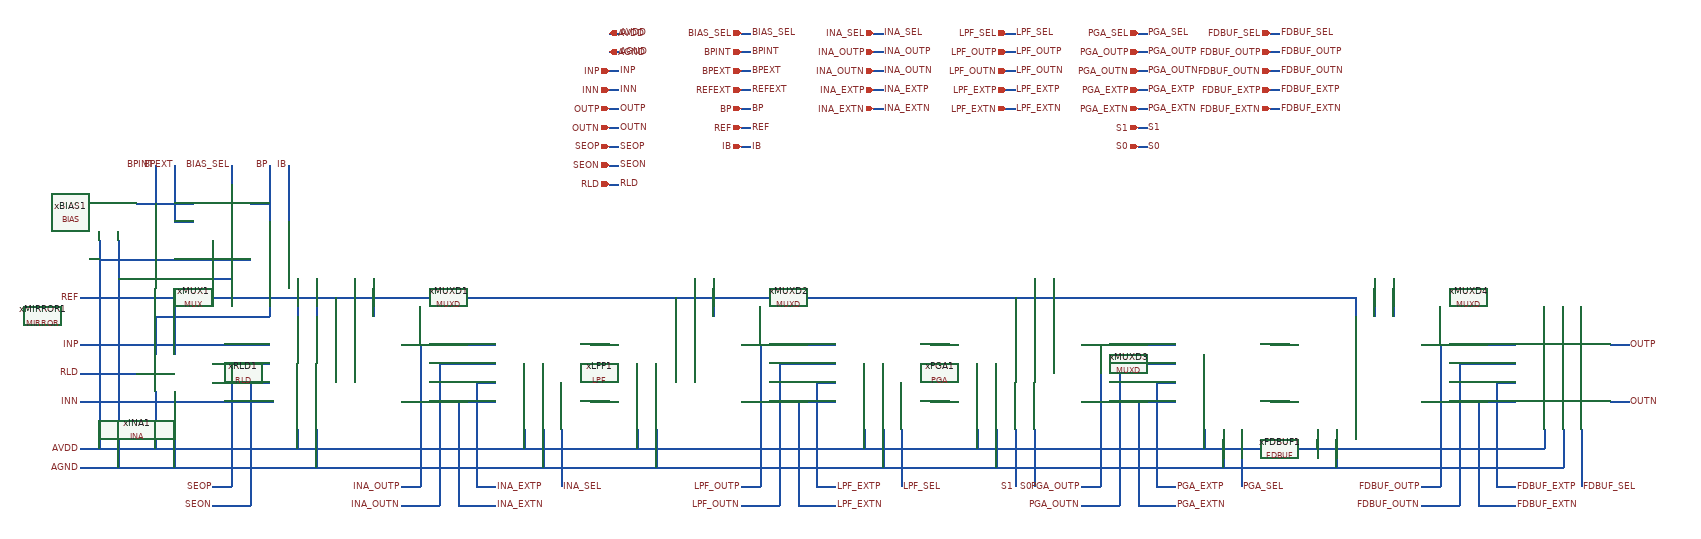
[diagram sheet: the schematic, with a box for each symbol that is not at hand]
v {xschem version=3.4.8RC file_version=1.3}
G {}
K {}
V {}
S {}
F {}
E {}
N 1880 -540 1920 -540 {lab=#net1}
N 1880 -420 1920 -420 {lab=#net2}
N 1160 -420 1200 -420 {lab=#net3}
N 1160 -540 1200 -540 {lab=#net4}
N 2600 -420 2640 -420 {lab=#net5}
N 2600 -540 2640 -540 {lab=#net6}
N 540 -360 540 -320 {lab=AVDD}
N 580 -360 580 -280 {lab=AGND}
N 2960 -540 2960 -240 {lab=FDBUF_OUTP}
N 2920 -420 3000 -420 {lab=FDBUF_OUTN}
N 3000 -500 3120 -500 {lab=FDBUF_OUTN}
N 3000 -500 3000 -200 {lab=FDBUF_OUTN}
N 2920 -540 3120 -540 {lab=FDBUF_OUTP}
N 2240 -540 2240 -240 {lab=PGA_OUTP}
N 2200 -420 2280 -420 {lab=PGA_OUTN}
N 2280 -500 2400 -500 {lab=PGA_OUTN}
N 2280 -500 2280 -200 {lab=PGA_OUTN}
N 2200 -540 2400 -540 {lab=PGA_OUTP}
N 1520 -540 1520 -240 {lab=LPF_OUTP}
N 1480 -420 1560 -420 {lab=LPF_OUTN}
N 1560 -500 1680 -500 {lab=LPF_OUTN}
N 1560 -500 1560 -200 {lab=LPF_OUTN}
N 1480 -540 1680 -540 {lab=LPF_OUTP}
N 800 -540 800 -240 {lab=INA_OUTP}
N 760 -420 840 -420 {lab=INA_OUTN}
N 840 -500 840 -200 {lab=INA_OUTN}
N 540 -680 540 -600 {lab=#net7}
N 580 -680 580 -600 {lab=#net8}
N 620 -640 620 -600 {lab=REF}
N 660 -680 660 -600 {lab=#net9}
N 700 -680 700 -600 {lab=#net10}
N 2780 -640 2780 -600 {lab=REF}
N 1340 -640 1340 -600 {lab=REF}
N 1380 -680 1380 -600 {lab=#net11}
N 1420 -680 1420 -600 {lab=#net12}
N 2100 -680 2100 -600 {lab=#net13}
N 2140 -680 2140 -600 {lab=#net14}
N 2060 -640 2060 -600 {lab=REF}
N 3220 -360 3220 -280 {lab=AGND}
N 3180 -360 3180 -320 {lab=AVDD}
N 1300 -360 1300 -280 {lab=AGND}
N 1060 -360 1060 -280 {lab=AGND}
N 1020 -360 1020 -320 {lab=AVDD}
N 1260 -360 1260 -320 {lab=AVDD}
N 1100 -360 1100 -240 {lab=INA_SEL}
N 1780 -360 1780 -280 {lab=AGND}
N 1740 -360 1740 -320 {lab=AVDD}
N 1820 -360 1820 -240 {lab=LPF_SEL}
N 2500 -360 2500 -280 {lab=AGND}
N 2460 -360 2460 -320 {lab=AVDD}
N 2540 -360 2540 -240 {lab=PGA_SEL}
N 3260 -360 3260 -240 {lab=FDBUF_SEL}
N 2740 -360 2740 -280 {lab=AGND}
N 2700 -360 2700 -320 {lab=AVDD}
N 2020 -360 2020 -280 {lab=AGND}
N 1980 -360 1980 -320 {lab=AVDD}
N 2060 -360 2060 -240 {lab=S1}
N 2100 -360 2100 -240 {lab=S0}
N 3320 -420 3360 -420 {lab=OUTN}
N 3320 -540 3360 -540 {lab=OUTP}
N 80 -280 3220 -280 {lab=AGND}
N 80 -320 3180 -320 {lab=AVDD}
N 360 -460 480 -460 {lab=SEON}
N 360 -500 480 -500 {lab=SEOP}
N 400 -500 400 -240 {lab=SEOP}
N 280 -640 280 -520 {lab=REF}
N 80 -640 2780 -640 {lab=REF}
N 240 -920 240 -840 {lab=BPINT}
N 280 -800 320 -800 {lab=BPEXT}
N 280 -920 280 -800 {lab=BPEXT}
N 200 -840 320 -840 {lab=BPINT}
N 2820 -680 2820 -600 {lab=#net15}
N 2860 -680 2860 -600 {lab=#net16}
N 360 -760 360 -720 {lab=AVDD}
N 400 -760 400 -680 {lab=AGND}
N 480 -920 480 -800 {lab=BP}
N 160 -680 400 -680 {lab=AGND}
N 120 -720 440 -720 {lab=AVDD}
N 120 -760 120 -320 {lab=AVDD}
N 160 -760 160 -280 {lab=AGND}
N 240 -440 240 -320 {lab=AVDD}
N 280 -440 280 -280 {lab=AGND}
N 1760 -1160 1780 -1160 {lab=INA_OUTP}
N 1760 -1120 1780 -1120 {lab=INA_OUTN}
N 1760 -1080 1780 -1080 {lab=INA_EXTP}
N 1760 -1040 1780 -1040 {lab=INA_EXTN}
N 2040 -1160 2060 -1160 {lab=LPF_OUTP}
N 2040 -1120 2060 -1120 {lab=LPF_OUTN}
N 2040 -1080 2060 -1080 {lab=LPF_EXTP}
N 2040 -1040 2060 -1040 {lab=LPF_EXTN}
N 2320 -1160 2340 -1160 {lab=PGA_OUTP}
N 2320 -1120 2340 -1120 {lab=PGA_OUTN}
N 2320 -1080 2340 -1080 {lab=PGA_EXTP}
N 2320 -1040 2340 -1040 {lab=PGA_EXTN}
N 2600 -1160 2620 -1160 {lab=FDBUF_OUTP}
N 2600 -1120 2620 -1120 {lab=FDBUF_OUTN}
N 2600 -1080 2620 -1080 {lab=FDBUF_EXTP}
N 2600 -1040 2620 -1040 {lab=FDBUF_EXTN}
N 1200 -1200 1220 -1200 {lab=AVDD}
N 1200 -1160 1220 -1160 {lab=AGND}
N 1200 -960 1220 -960 {lab=SEOP}
N 1200 -920 1220 -920 {lab=SEON}
N 1200 -880 1220 -880 {lab=RLD}
N 1200 -1120 1220 -1120 {lab=INP}
N 1200 -1080 1220 -1080 {lab=INN}
N 1480 -1160 1500 -1160 {lab=BPINT}
N 1480 -1120 1500 -1120 {lab=BPEXT}
N 1480 -1080 1500 -1080 {lab=REFEXT}
N 1480 -1200 1500 -1200 {lab=BIAS_SEL}
N 1480 -1040 1500 -1040 {lab=BP}
N 1480 -1000 1500 -1000 {lab=REF}
N 1760 -1200 1780 -1200 {lab=INA_SEL}
N 2040 -1200 2060 -1200 {lab=LPF_SEL}
N 2320 -1200 2340 -1200 {lab=PGA_SEL}
N 2320 -1000 2340 -1000 {lab=S1}
N 2320 -960 2340 -960 {lab=S0}
N 2600 -1200 2620 -1200 {lab=FDBUF_SEL}
N 1200 -1040 1220 -1040 {lab=OUTP}
N 1200 -1000 1220 -1000 {lab=OUTN}
N 1480 -960 1500 -960 {lab=IB}
N 520 -920 520 -800 {lab=IB}
N 400 -920 400 -880 {lab=BIAS_SEL}
N 80 -540 480 -540 {lab=INP}
N 80 -480 200 -480 {lab=RLD}
N 80 -420 490 -420 {lab=INN}
N 880 -420 880 -200 {lab=INA_EXTN}
N 920 -460 920 -240 {lab=INA_EXTP}
N 760 -540 960 -540 {lab=INA_OUTP}
N 840 -500 960 -500 {lab=INA_OUTN}
N 760 -240 800 -240 {lab=INA_OUTP}
N 760 -200 840 -200 {lab=INA_OUTN}
N 880 -420 960 -420 {lab=INA_EXTN}
N 920 -460 960 -460 {lab=INA_EXTP}
N 880 -200 960 -200 {lab=INA_EXTN}
N 920 -240 960 -240 {lab=INA_EXTP}
N 1480 -240 1520 -240 {lab=LPF_OUTP}
N 1480 -200 1560 -200 {lab=LPF_OUTN}
N 1600 -420 1680 -420 {lab=LPF_EXTN}
N 1600 -420 1600 -200 {lab=LPF_EXTN}
N 1600 -200 1680 -200 {lab=LPF_EXTN}
N 1640 -240 1680 -240 {lab=LPF_EXTP}
N 1640 -460 1640 -240 {lab=LPF_EXTP}
N 1640 -460 1680 -460 {lab=LPF_EXTP}
N 2200 -240 2240 -240 {lab=PGA_OUTP}
N 2200 -200 2280 -200 {lab=PGA_OUTN}
N 2360 -460 2400 -460 {lab=PGA_EXTP}
N 2360 -460 2360 -240 {lab=PGA_EXTP}
N 2360 -240 2400 -240 {lab=PGA_EXTP}
N 2320 -200 2400 -200 {lab=PGA_EXTN}
N 2320 -420 2320 -200 {lab=PGA_EXTN}
N 2320 -420 2400 -420 {lab=PGA_EXTN}
N 2920 -240 2960 -240 {lab=FDBUF_OUTP}
N 2920 -200 3000 -200 {lab=FDBUF_OUTN}
N 3080 -460 3120 -460 {lab=FDBUF_EXTP}
N 3080 -460 3080 -240 {lab=FDBUF_EXTP}
N 3080 -240 3120 -240 {lab=FDBUF_EXTP}
N 3040 -200 3120 -200 {lab=FDBUF_EXTN}
N 3040 -420 3040 -200 {lab=FDBUF_EXTN}
N 3040 -420 3120 -420 {lab=FDBUF_EXTN}
N 480 -680 480 -600 {lab=#net17}
N 240 -600 480 -600 {lab=#net17}
N 240 -600 240 -520 {lab=#net17}
N 440 -840 480 -840 {lab=BP}
N 360 -240 400 -240 {lab=SEOP}
N 360 -200 440 -200 {lab=SEON}
N 440 -460 440 -200 {lab=SEON}
C {title.sym} 160 -40 0 0 {name=l1 author="Yi-Hsiang Wei"}
C {lab_wire.sym} 80 -540 0 0 {name=p6 sig_type=std_logic lab=INP}
C {lab_wire.sym} 80 -420 0 0 {name=p7 sig_type=std_logic lab=INN}
C {lab_wire.sym} 3360 -540 0 1 {name=p20 sig_type=std_logic lab=OUTP}
C {lab_wire.sym} 3360 -420 0 1 {name=p21 sig_type=std_logic lab=OUTN}
C {ECG_Acquisition_IC/Design_Files/IC Design/Schematic/AFE_BLOCKS/LPF/LPF.sym} 1140 -320 0 0 {name=xLFP1}
C {ECG_Acquisition_IC/Design_Files/IC Design/Schematic/AFE_BLOCKS/PGA/PGA.sym} 1860 -320 0 0 {name=xPGA1}
C {ECG_Acquisition_IC/Design_Files/IC Design/Schematic/DIGITAL_BLOCKS/MUXD/MUXD.sym} 900 -320 0 0 {name=xMUXD1}
C {ECG_Acquisition_IC/Design_Files/IC Design/Schematic/AFE_BLOCKS/INA/INA.sym} 420 -320 0 0 {name=xINA1}
C {ECG_Acquisition_IC/Design_Files/IC Design/Schematic/DIGITAL_BLOCKS/MUXD/MUXD.sym} 1620 -320 0 0 {name=xMUXD2}
C {ECG_Acquisition_IC/Design_Files/IC Design/Schematic/DIGITAL_BLOCKS/MUXD/MUXD.sym} 2340 -320 0 0 {name=xMUXD3}
C {ECG_Acquisition_IC/Design_Files/IC Design/Schematic/DIGITAL_BLOCKS/MUXD/MUXD.sym} 3060 -320 0 0 {name=xMUXD4}
C {lab_wire.sym} 360 -240 0 0 {name=p94 sig_type=std_logic lab=SEOP}
C {lab_wire.sym} 360 -200 0 0 {name=p95 sig_type=std_logic lab=SEON}
C {lab_wire.sym} 760 -240 0 0 {name=p38 sig_type=std_logic lab=INA_OUTP}
C {lab_wire.sym} 760 -200 0 0 {name=p43 sig_type=std_logic lab=INA_OUTN}
C {lab_wire.sym} 1100 -240 2 0 {name=p46 sig_type=std_logic lab=INA_SEL}
C {lab_wire.sym} 1480 -240 0 0 {name=p47 sig_type=std_logic lab=LPF_OUTP}
C {lab_wire.sym} 1480 -200 0 0 {name=p48 sig_type=std_logic lab=LPF_OUTN}
C {lab_wire.sym} 960 -240 0 1 {name=p49 sig_type=std_logic lab=INA_EXTP}
C {lab_wire.sym} 960 -200 0 1 {name=p51 sig_type=std_logic lab=INA_EXTN}
C {lab_wire.sym} 2200 -240 0 0 {name=p62 sig_type=std_logic lab=PGA_OUTP}
C {lab_wire.sym} 2200 -200 0 0 {name=p67 sig_type=std_logic lab=PGA_OUTN}
C {lab_wire.sym} 1680 -240 0 1 {name=p70 sig_type=std_logic lab=LPF_EXTP}
C {lab_wire.sym} 1680 -200 0 1 {name=p80 sig_type=std_logic lab=LPF_EXTN}
C {lab_wire.sym} 1820 -240 2 0 {name=p82 sig_type=std_logic lab=LPF_SEL}
C {lab_wire.sym} 2060 -240 2 1 {name=p83 sig_type=std_logic lab=S1}
C {lab_wire.sym} 2100 -240 2 1 {name=p84 sig_type=std_logic lab=S0}
C {lab_wire.sym} 2540 -240 2 0 {name=p85 sig_type=std_logic lab=PGA_SEL}
C {lab_wire.sym} 3260 -240 2 0 {name=p87 sig_type=std_logic lab=FDBUF_SEL}
C {lab_wire.sym} 2920 -240 0 0 {name=p92 sig_type=std_logic lab=FDBUF_OUTP}
C {lab_wire.sym} 2920 -200 0 0 {name=p93 sig_type=std_logic lab=FDBUF_OUTN}
C {lab_wire.sym} 2400 -240 0 1 {name=p100 sig_type=std_logic lab=PGA_EXTP}
C {lab_wire.sym} 2400 -200 0 1 {name=p101 sig_type=std_logic lab=PGA_EXTN}
C {lab_wire.sym} 3120 -240 0 1 {name=p132 sig_type=std_logic lab=FDBUF_EXTP}
C {lab_wire.sym} 3120 -200 0 1 {name=p133 sig_type=std_logic lab=FDBUF_EXTN}
C {lab_wire.sym} 80 -480 0 0 {name=p168 sig_type=std_logic lab=RLD}
C {ECG_Acquisition_IC/Design_Files/IC Design/Schematic/AFE_BLOCKS/RLD/RLD.sym} 440 -340 0 1 {name=xRLD1}
C {ECG_Acquisition_IC/Design_Files/IC Design/Schematic/AFE_BLOCKS/BIAS/BIAS.sym} 40 -720 0 0 {name=xBIAS1}
C {lab_wire.sym} 80 -320 0 0 {name=p31 sig_type=std_logic lab=AVDD}
C {lab_wire.sym} 80 -280 0 0 {name=p32 sig_type=std_logic lab=AGND}
C {lab_wire.sym} 400 -920 0 0 {name=p33 sig_type=std_logic lab=BIAS_SEL}
C {lab_wire.sym} 280 -920 0 0 {name=p36 sig_type=std_logic lab=BPEXT}
C {lab_wire.sym} 240 -920 0 0 {name=p53 sig_type=std_logic lab=BPINT}
C {lab_wire.sym} 80 -640 0 0 {name=p34 sig_type=std_logic lab=REF}
C {lab_wire.sym} 480 -920 0 0 {name=p35 sig_type=std_logic lab=BP}
C {ECG_Acquisition_IC/Design_Files/IC Design/Schematic/AFE_BLOCKS/MIRROR/MIRROR.sym} 0 -600 0 0 {name=xMIRROR1}
C {opin.sym} 1760 -1160 0 1 {name=p102 lab=INA_OUTP}
C {opin.sym} 1760 -1120 0 1 {name=p103 lab=INA_OUTN}
C {lab_wire.sym} 1780 -1160 0 1 {name=p104 sig_type=std_logic lab=INA_OUTP}
C {lab_wire.sym} 1780 -1120 0 1 {name=p105 sig_type=std_logic lab=INA_OUTN}
C {ipin.sym} 1760 -1080 0 0 {name=p106 lab=INA_EXTP}
C {ipin.sym} 1760 -1040 0 0 {name=p107 lab=INA_EXTN}
C {lab_wire.sym} 1780 -1080 0 1 {name=p108 sig_type=std_logic lab=INA_EXTP}
C {lab_wire.sym} 1780 -1040 0 1 {name=p109 sig_type=std_logic lab=INA_EXTN}
C {opin.sym} 2040 -1160 0 1 {name=p110 lab=LPF_OUTP}
C {opin.sym} 2040 -1120 0 1 {name=p111 lab=LPF_OUTN}
C {lab_wire.sym} 2060 -1160 0 1 {name=p112 sig_type=std_logic lab=LPF_OUTP}
C {lab_wire.sym} 2060 -1120 0 1 {name=p113 sig_type=std_logic lab=LPF_OUTN}
C {ipin.sym} 2040 -1080 0 0 {name=p114 lab=LPF_EXTP}
C {ipin.sym} 2040 -1040 0 0 {name=p115 lab=LPF_EXTN}
C {lab_wire.sym} 2060 -1080 0 1 {name=p116 sig_type=std_logic lab=LPF_EXTP}
C {lab_wire.sym} 2060 -1040 0 1 {name=p117 sig_type=std_logic lab=LPF_EXTN}
C {opin.sym} 2320 -1160 0 1 {name=p118 lab=PGA_OUTP}
C {opin.sym} 2320 -1120 0 1 {name=p119 lab=PGA_OUTN}
C {lab_wire.sym} 2340 -1160 0 1 {name=p120 sig_type=std_logic lab=PGA_OUTP}
C {lab_wire.sym} 2340 -1120 0 1 {name=p121 sig_type=std_logic lab=PGA_OUTN}
C {ipin.sym} 2320 -1080 0 0 {name=p122 lab=PGA_EXTP}
C {ipin.sym} 2320 -1040 0 0 {name=p123 lab=PGA_EXTN}
C {lab_wire.sym} 2340 -1080 0 1 {name=p124 sig_type=std_logic lab=PGA_EXTP}
C {lab_wire.sym} 2340 -1040 0 1 {name=p125 sig_type=std_logic lab=PGA_EXTN}
C {opin.sym} 2600 -1160 0 1 {name=p147 lab=FDBUF_OUTP}
C {opin.sym} 2600 -1120 0 1 {name=p148 lab=FDBUF_OUTN}
C {lab_wire.sym} 2620 -1160 0 1 {name=p149 sig_type=std_logic lab=FDBUF_OUTP}
C {lab_wire.sym} 2620 -1120 0 1 {name=p150 sig_type=std_logic lab=FDBUF_OUTN}
C {ipin.sym} 2600 -1080 0 0 {name=p151 lab=FDBUF_EXTP}
C {ipin.sym} 2600 -1040 0 0 {name=p152 lab=FDBUF_EXTN}
C {lab_wire.sym} 2620 -1080 0 1 {name=p153 sig_type=std_logic lab=FDBUF_EXTP}
C {lab_wire.sym} 2620 -1040 0 1 {name=p154 sig_type=std_logic lab=FDBUF_EXTN}
C {iopin.sym} 1200 -1200 0 1 {name=p158 lab=AVDD}
C {iopin.sym} 1200 -1160 0 1 {name=p159 lab=AGND}
C {lab_wire.sym} 1220 -1200 0 1 {name=p160 sig_type=std_logic lab=AVDD}
C {lab_wire.sym} 1220 -1160 0 1 {name=p161 sig_type=std_logic lab=AGND}
C {opin.sym} 1200 -960 0 1 {name=p162 lab=SEOP}
C {opin.sym} 1200 -920 0 1 {name=p163 lab=SEON}
C {lab_wire.sym} 1220 -960 0 1 {name=p164 sig_type=std_logic lab=SEOP}
C {lab_wire.sym} 1220 -920 0 1 {name=p165 sig_type=std_logic lab=SEON}
C {opin.sym} 1200 -880 0 1 {name=p166 lab=RLD}
C {lab_wire.sym} 1220 -880 0 1 {name=p167 sig_type=std_logic lab=RLD}
C {ipin.sym} 1200 -1120 0 0 {name=p1 lab=INP}
C {ipin.sym} 1200 -1080 0 0 {name=p2 lab=INN}
C {lab_wire.sym} 1220 -1120 0 1 {name=p3 sig_type=std_logic lab=INP}
C {lab_wire.sym} 1220 -1080 0 1 {name=p4 sig_type=std_logic lab=INN}
C {opin.sym} 1480 -1160 0 1 {name=p5 lab=BPINT}
C {lab_wire.sym} 1500 -1160 0 1 {name=p9 sig_type=std_logic lab=BPINT}
C {ipin.sym} 1480 -1120 0 0 {name=p11 lab=BPEXT}
C {ipin.sym} 1480 -1080 0 0 {name=p12 lab=REFEXT}
C {lab_wire.sym} 1500 -1120 0 1 {name=p13 sig_type=std_logic lab=BPEXT}
C {lab_wire.sym} 1500 -1080 0 1 {name=p14 sig_type=std_logic lab=REFEXT}
C {ipin.sym} 1480 -1200 0 0 {name=p15 lab=BIAS_SEL}
C {lab_wire.sym} 1500 -1200 0 1 {name=p16 sig_type=std_logic lab=BIAS_SEL}
C {opin.sym} 1480 -1040 0 1 {name=p17 lab=BP}
C {opin.sym} 1480 -1000 0 1 {name=p18 lab=REF}
C {lab_wire.sym} 1500 -1040 0 1 {name=p19 sig_type=std_logic lab=BP}
C {lab_wire.sym} 1500 -1000 0 1 {name=p22 sig_type=std_logic lab=REF}
C {ipin.sym} 1760 -1200 0 0 {name=p23 lab=INA_SEL}
C {lab_wire.sym} 1780 -1200 0 1 {name=p24 sig_type=std_logic lab=INA_SEL}
C {ipin.sym} 2040 -1200 0 0 {name=p25 lab=LPF_SEL}
C {lab_wire.sym} 2060 -1200 0 1 {name=p26 sig_type=std_logic lab=LPF_SEL}
C {ipin.sym} 2320 -1200 0 0 {name=p27 lab=PGA_SEL}
C {lab_wire.sym} 2340 -1200 0 1 {name=p28 sig_type=std_logic lab=PGA_SEL}
C {ipin.sym} 2320 -1000 0 0 {name=p29 lab=S1}
C {lab_wire.sym} 2340 -1000 0 1 {name=p30 sig_type=std_logic lab=S1}
C {ipin.sym} 2320 -960 0 0 {name=p37 lab=S0}
C {lab_wire.sym} 2340 -960 0 1 {name=p39 sig_type=std_logic lab=S0}
C {ipin.sym} 2600 -1200 0 0 {name=p40 lab=FDBUF_SEL}
C {lab_wire.sym} 2620 -1200 0 1 {name=p41 sig_type=std_logic lab=FDBUF_SEL}
C {opin.sym} 1200 -1040 0 1 {name=p42 lab=OUTP}
C {opin.sym} 1200 -1000 0 1 {name=p44 lab=OUTN}
C {lab_wire.sym} 1220 -1040 0 1 {name=p45 sig_type=std_logic lab=OUTP}
C {lab_wire.sym} 1220 -1000 0 1 {name=p50 sig_type=std_logic lab=OUTN}
C {opin.sym} 1480 -960 0 1 {name=p52 lab=IB}
C {lab_wire.sym} 1500 -960 0 1 {name=p54 sig_type=std_logic lab=IB}
C {lab_wire.sym} 520 -920 0 0 {name=p55 sig_type=std_logic lab=IB}
C {ECG_Acquisition_IC/Design_Files/IC Design/Schematic/DIGITAL_BLOCKS/MUX/MUX.sym} 240 -640 0 0 {name=xMUX1}
C {ECG_Acquisition_IC/Design_Files/IC Design/Schematic/AFE_BLOCKS/FDBUF/FDBUF.sym} 2580 -320 0 0 {name=xFDBUF1}
